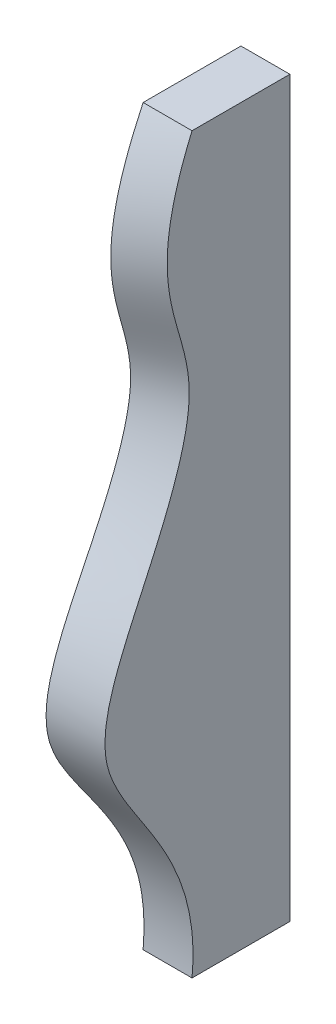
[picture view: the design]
ISO-10303-21;
HEADER;
FILE_DESCRIPTION(('STEP AP214'),'2;1');
FILE_NAME('part.step','',(''),(''),'','','');
FILE_SCHEMA(('AUTOMOTIVE_DESIGN { 1 0 10303 214 1 1 1 1 }'));
ENDSEC;
DATA;
#1=APPLICATION_CONTEXT('core data for automotive mechanical design processes');
#2=APPLICATION_PROTOCOL_DEFINITION('international standard','automotive_design',2000,#1);
#3=PRODUCT_CONTEXT('',#1,'mechanical');
#4=PRODUCT('Part','Part','',(#3));
#5=PRODUCT_RELATED_PRODUCT_CATEGORY('part','',(#4));
#6=PRODUCT_DEFINITION_FORMATION('','',#4);
#7=PRODUCT_DEFINITION_CONTEXT('part definition',#1,'design');
#8=PRODUCT_DEFINITION('design','',#6,#7);
#9=PRODUCT_DEFINITION_SHAPE('','',#8);
#10=(LENGTH_UNIT() NAMED_UNIT(*) SI_UNIT(.MILLI.,.METRE.));
#11=(NAMED_UNIT(*) PLANE_ANGLE_UNIT() SI_UNIT($,.RADIAN.));
#12=(NAMED_UNIT(*) SI_UNIT($,.STERADIAN.) SOLID_ANGLE_UNIT());
#13=UNCERTAINTY_MEASURE_WITH_UNIT(LENGTH_MEASURE(1.E-05),#10,'distance_accuracy_value','');
#14=(GEOMETRIC_REPRESENTATION_CONTEXT(3) GLOBAL_UNCERTAINTY_ASSIGNED_CONTEXT((#13)) GLOBAL_UNIT_ASSIGNED_CONTEXT((#10,
#11,#12)) REPRESENTATION_CONTEXT('',''));
#15=CARTESIAN_POINT('',(0.,0.,0.));
#16=DIRECTION('',(0.,0.,1.));
#17=DIRECTION('',(1.,0.,0.));
#18=AXIS2_PLACEMENT_3D('',#15,#16,#17);
#19=CARTESIAN_POINT('',(350.,375.,253.120113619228));
#20=DIRECTION('',(1.,0.,0.));
#21=DIRECTION('',(0.,0.,-1.));
#22=AXIS2_PLACEMENT_3D('',#19,#20,#21);
#23=PLANE('',#22);
#24=CARTESIAN_POINT('',(350.,375.,100.));
#25=CARTESIAN_POINT('',(350.,373.120513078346,100.80507653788));
#26=CARTESIAN_POINT('',(350.,371.235951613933,101.598369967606));
#27=CARTESIAN_POINT('',(350.,367.454003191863,103.160628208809));
#28=CARTESIAN_POINT('',(350.,365.556603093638,103.929561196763));
#29=CARTESIAN_POINT('',(350.,361.749341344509,105.4409716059));
#30=CARTESIAN_POINT('',(350.,359.839470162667,106.183425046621));
#31=CARTESIAN_POINT('',(350.,356.007596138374,107.639611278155));
#32=CARTESIAN_POINT('',(350.,354.085587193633,108.353328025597));
#33=CARTESIAN_POINT('',(350.,350.229725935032,109.749678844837));
#34=CARTESIAN_POINT('',(350.,348.29587063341,110.432304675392));
#35=CARTESIAN_POINT('',(350.,344.416561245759,111.763993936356));
#36=CARTESIAN_POINT('',(350.,342.471106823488,112.413056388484));
#37=CARTESIAN_POINT('',(350.,338.582432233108,113.670607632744));
#38=CARTESIAN_POINT('',(350.,336.639295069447,114.279352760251));
#39=CARTESIAN_POINT('',(350.,332.741854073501,115.458529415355));
#40=CARTESIAN_POINT('',(350.,330.787552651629,116.02896889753));
#41=CARTESIAN_POINT('',(350.,326.867865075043,117.128727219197));
#42=CARTESIAN_POINT('',(350.,324.902481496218,117.658055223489));
#43=CARTESIAN_POINT('',(350.,320.960675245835,118.672642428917));
#44=CARTESIAN_POINT('',(350.,318.984254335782,119.157908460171));
#45=CARTESIAN_POINT('',(350.,315.020382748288,120.081283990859));
#46=CARTESIAN_POINT('',(350.,313.03293196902,120.519393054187));
#47=CARTESIAN_POINT('',(350.,309.046977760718,121.345234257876));
#48=CARTESIAN_POINT('',(350.,307.048471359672,121.732952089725));
#49=CARTESIAN_POINT('',(350.,303.003435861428,122.461320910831));
#50=CARTESIAN_POINT('',(350.,300.95671871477,122.800931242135));
#51=CARTESIAN_POINT('',(350.,296.853711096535,123.420517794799));
#52=CARTESIAN_POINT('',(350.,294.797418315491,123.700478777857));
#53=CARTESIAN_POINT('',(350.,290.677198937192,124.197048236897));
#54=CARTESIAN_POINT('',(350.,288.613272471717,124.413657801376));
#55=CARTESIAN_POINT('',(350.,284.479758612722,124.780113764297));
#56=CARTESIAN_POINT('',(350.,282.410172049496,124.929969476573));
#57=CARTESIAN_POINT('',(350.,278.267354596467,125.159951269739));
#58=CARTESIAN_POINT('',(350.,276.194124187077,125.240085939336));
#59=CARTESIAN_POINT('',(350.,272.046096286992,125.328271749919));
#60=CARTESIAN_POINT('',(350.,269.971298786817,125.336322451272));
#61=CARTESIAN_POINT('',(350.,265.809538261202,125.278622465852));
#62=CARTESIAN_POINT('',(350.,263.722581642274,125.212402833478));
#63=CARTESIAN_POINT('',(350.,259.551809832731,125.004945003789));
#64=CARTESIAN_POINT('',(350.,257.467995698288,124.863685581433));
#65=CARTESIAN_POINT('',(350.,253.306517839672,124.507067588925));
#66=CARTESIAN_POINT('',(350.,251.228854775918,124.291701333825));
#67=CARTESIAN_POINT('',(350.,247.082496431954,123.789442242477));
#68=CARTESIAN_POINT('',(350.,245.01380004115,123.502558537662));
#69=CARTESIAN_POINT('',(350.,240.887980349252,122.861678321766));
#70=CARTESIAN_POINT('',(350.,238.830851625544,122.507716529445));
#71=CARTESIAN_POINT('',(350.,234.730516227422,121.739032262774));
#72=CARTESIAN_POINT('',(350.,232.687296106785,121.324381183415));
#73=CARTESIAN_POINT('',(350.,229.324667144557,120.596020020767));
#74=CARTESIAN_POINT('',(350.,228.001889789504,120.297687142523));
#75=CARTESIAN_POINT('',(350.,225.361008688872,119.680960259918));
#76=CARTESIAN_POINT('',(350.,224.042904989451,119.362566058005));
#77=CARTESIAN_POINT('',(350.,221.411649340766,118.708615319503));
#78=CARTESIAN_POINT('',(350.,220.098495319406,118.373067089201));
#79=CARTESIAN_POINT('',(350.,217.475944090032,117.687649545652));
#80=CARTESIAN_POINT('',(350.,216.166546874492,117.337780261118));
#81=CARTESIAN_POINT('',(350.,213.550150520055,116.626740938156));
#82=CARTESIAN_POINT('',(350.,212.243152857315,116.265565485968));
#83=CARTESIAN_POINT('',(350.,209.631330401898,115.535463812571));
#84=CARTESIAN_POINT('',(350.,208.326505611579,115.166537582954));
#85=CARTESIAN_POINT('',(350.,205.716806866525,114.424129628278));
#86=CARTESIAN_POINT('',(350.,204.411934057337,114.050643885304));
#87=CARTESIAN_POINT('',(350.,201.802338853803,113.303162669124));
#88=CARTESIAN_POINT('',(350.,200.497616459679,112.929167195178));
#89=CARTESIAN_POINT('',(350.,196.578841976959,111.811199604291));
#90=CARTESIAN_POINT('',(350.,193.963342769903,111.072165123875));
#91=CARTESIAN_POINT('',(350.,190.028741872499,109.996369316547));
#92=CARTESIAN_POINT('',(350.,188.714219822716,109.642950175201));
#93=CARTESIAN_POINT('',(350.,186.08121307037,108.951229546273));
#94=CARTESIAN_POINT('',(350.,184.762728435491,108.612927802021));
#95=CARTESIAN_POINT('',(350.,182.149843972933,107.962512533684));
#96=CARTESIAN_POINT('',(350.,180.855546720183,107.649988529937));
#97=CARTESIAN_POINT('',(350.,178.261875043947,107.046685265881));
#98=CARTESIAN_POINT('',(350.,176.962500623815,106.755905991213));
#99=CARTESIAN_POINT('',(350.,174.35803960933,106.199429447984));
#100=CARTESIAN_POINT('',(350.,173.052951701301,105.933738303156));
#101=CARTESIAN_POINT('',(350.,170.437300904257,105.430717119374));
#102=CARTESIAN_POINT('',(350.,169.126738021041,105.193387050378));
#103=CARTESIAN_POINT('',(350.,166.502305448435,104.750354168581));
#104=CARTESIAN_POINT('',(350.,165.188443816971,104.544603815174));
#105=CARTESIAN_POINT('',(350.,162.555853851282,104.166888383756));
#106=CARTESIAN_POINT('',(350.,161.237125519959,103.9949232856));
#107=CARTESIAN_POINT('',(350.,158.598179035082,103.687308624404));
#108=CARTESIAN_POINT('',(350.,157.277969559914,103.551584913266));
#109=CARTESIAN_POINT('',(350.,154.634210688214,103.317771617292));
#110=CARTESIAN_POINT('',(350.,153.310661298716,103.219681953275));
#111=CARTESIAN_POINT('',(350.,150.663516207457,103.062615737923));
#112=CARTESIAN_POINT('',(350.,149.33992449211,103.003572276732));
#113=CARTESIAN_POINT('',(350.,146.691551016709,102.92521689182));
#114=CARTESIAN_POINT('',(350.,145.366769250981,102.905905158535));
#115=CARTESIAN_POINT('',(350.,142.718527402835,102.907471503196));
#116=CARTESIAN_POINT('',(350.,141.395067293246,102.928310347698));
#117=CARTESIAN_POINT('',(350.,138.749368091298,103.010106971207));
#118=CARTESIAN_POINT('',(350.,137.427128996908,103.071064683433));
#119=CARTESIAN_POINT('',(350.,135.435972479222,103.193010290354));
#120=CARTESIAN_POINT('',(350.,134.766115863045,103.239187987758));
#121=CARTESIAN_POINT('',(350.,133.427178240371,103.341422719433));
#122=CARTESIAN_POINT('',(350.,132.758097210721,103.397479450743));
#123=CARTESIAN_POINT('',(350.,130.752093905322,103.57967287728));
#124=CARTESIAN_POINT('',(350.,129.416427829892,103.719831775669));
#125=CARTESIAN_POINT('',(350.,126.746077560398,104.034330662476));
#126=CARTESIAN_POINT('',(350.,125.411402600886,104.208748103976));
#127=CARTESIAN_POINT('',(350.,122.746472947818,104.588426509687));
#128=CARTESIAN_POINT('',(350.,121.416218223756,104.79368726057));
#129=CARTESIAN_POINT('',(350.,118.756687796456,105.232928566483));
#130=CARTESIAN_POINT('',(350.,117.427425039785,105.466987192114));
#131=CARTESIAN_POINT('',(350.,114.773725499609,105.960958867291));
#132=CARTESIAN_POINT('',(350.,113.449288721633,106.220871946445));
#133=CARTESIAN_POINT('',(350.,110.802364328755,106.765040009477));
#134=CARTESIAN_POINT('',(350.,109.479887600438,107.049347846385));
#135=CARTESIAN_POINT('',(350.,106.839864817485,107.63991702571));
#136=CARTESIAN_POINT('',(350.,105.522318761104,107.946178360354));
#137=CARTESIAN_POINT('',(350.,101.574233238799,108.896112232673));
#138=CARTESIAN_POINT('',(350.,98.9510090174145,109.570359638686));
#139=CARTESIAN_POINT('',(350.,93.7251831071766,110.989597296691));
#140=CARTESIAN_POINT('',(350.,91.1225726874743,111.734555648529));
#141=CARTESIAN_POINT('',(350.,85.8499915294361,113.312392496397));
#142=CARTESIAN_POINT('',(350.,83.1806497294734,114.147367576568));
#143=CARTESIAN_POINT('',(350.,77.866351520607,115.873525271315));
#144=CARTESIAN_POINT('',(350.,75.2213561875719,116.764588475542));
#145=CARTESIAN_POINT('',(350.,69.952539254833,118.59600626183));
#146=CARTESIAN_POINT('',(350.,67.3286938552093,119.536292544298));
#147=CARTESIAN_POINT('',(350.,62.0993206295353,121.460166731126));
#148=CARTESIAN_POINT('',(350.,59.493779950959,122.443719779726));
#149=CARTESIAN_POINT('',(350.,54.2984144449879,124.448835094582));
#150=CARTESIAN_POINT('',(350.,51.7085845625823,125.470384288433));
#151=CARTESIAN_POINT('',(350.,46.5422302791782,127.546711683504));
#152=CARTESIAN_POINT('',(350.,43.9657062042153,128.601490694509));
#153=CARTESIAN_POINT('',(350.,38.6826536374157,130.798510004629));
#154=CARTESIAN_POINT('',(350.,35.976797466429,131.942364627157));
#155=CARTESIAN_POINT('',(350.,30.575370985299,134.256979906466));
#156=CARTESIAN_POINT('',(350.,27.8798051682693,135.427751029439));
#157=CARTESIAN_POINT('',(350.,22.4971061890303,137.791144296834));
#158=CARTESIAN_POINT('',(350.,19.8099764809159,138.983774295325));
#159=CARTESIAN_POINT('',(350.,14.4423010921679,141.385833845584));
#160=CARTESIAN_POINT('',(350.,11.7617575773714,142.595268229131));
#161=CARTESIAN_POINT('',(350.,6.40535766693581,145.025776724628));
#162=CARTESIAN_POINT('',(350.,3.72950224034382,146.246852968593));
#163=CARTESIAN_POINT('',(350.,-1.61951759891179,148.695262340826));
#164=CARTESIAN_POINT('',(350.,-4.2926818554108,149.922595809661));
#165=CARTESIAN_POINT('',(350.,-9.60700695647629,152.363341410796));
#166=CARTESIAN_POINT('',(350.,-12.2481712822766,153.576745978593));
#167=CARTESIAN_POINT('',(350.,-17.5324930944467,155.998195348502));
#168=CARTESIAN_POINT('',(350.,-20.1756502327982,157.206240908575));
#169=CARTESIAN_POINT('',(350.,-25.4667510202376,159.61049346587));
#170=CARTESIAN_POINT('',(350.,-28.1146936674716,160.806702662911));
#171=CARTESIAN_POINT('',(350.,-33.4185081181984,163.180023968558));
#172=CARTESIAN_POINT('',(350.,-36.0743782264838,164.357139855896));
#173=CARTESIAN_POINT('',(350.,-41.3976371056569,166.684025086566));
#174=CARTESIAN_POINT('',(350.,-44.0650241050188,167.833798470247));
#175=CARTESIAN_POINT('',(350.,-49.4154660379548,170.096498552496));
#176=CARTESIAN_POINT('',(350.,-52.09852113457,171.20942486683));
#177=CARTESIAN_POINT('',(350.,-57.224772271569,173.282062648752));
#178=CARTESIAN_POINT('',(350.,-59.666168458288,174.246204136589));
#179=CARTESIAN_POINT('',(350.,-63.3426312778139,175.655331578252));
#180=CARTESIAN_POINT('',(350.,-64.5705891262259,176.11888712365));
#181=CARTESIAN_POINT('',(350.,-67.0316262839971,177.032183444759));
#182=CARTESIAN_POINT('',(350.,-68.2647055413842,177.481924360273));
#183=CARTESIAN_POINT('',(350.,-70.7366637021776,178.366173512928));
#184=CARTESIAN_POINT('',(350.,-71.9755439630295,178.800677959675));
#185=CARTESIAN_POINT('',(350.,-74.4591336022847,179.652659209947));
#186=CARTESIAN_POINT('',(350.,-75.7038428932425,180.070136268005));
#187=CARTESIAN_POINT('',(350.,-78.2042178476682,180.887818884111));
#188=CARTESIAN_POINT('',(350.,-79.4599072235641,181.287952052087));
#189=CARTESIAN_POINT('',(350.,-81.9777631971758,182.067232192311));
#190=CARTESIAN_POINT('',(350.,-83.2399296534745,182.446379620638));
#191=CARTESIAN_POINT('',(350.,-85.7708333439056,183.18148401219));
#192=CARTESIAN_POINT('',(350.,-87.0395696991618,183.53744399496));
#193=CARTESIAN_POINT('',(350.,-89.5839467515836,184.223888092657));
#194=CARTESIAN_POINT('',(350.,-90.8595875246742,184.554371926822));
#195=CARTESIAN_POINT('',(350.,-93.4175328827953,185.187261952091));
#196=CARTESIAN_POINT('',(350.,-94.6998359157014,185.489674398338));
#197=CARTESIAN_POINT('',(350.,-97.2712641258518,186.063782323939));
#198=CARTESIAN_POINT('',(350.,-98.5603890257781,186.335479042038));
#199=CARTESIAN_POINT('',(350.,-101.248551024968,186.865648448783));
#200=CARTESIAN_POINT('',(350.,-102.648141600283,187.121330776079));
#201=CARTESIAN_POINT('',(350.,-105.454585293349,187.58968211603));
#202=CARTESIAN_POINT('',(350.,-106.861438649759,187.802349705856));
#203=CARTESIAN_POINT('',(350.,-109.681510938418,188.180627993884));
#204=CARTESIAN_POINT('',(350.,-111.094729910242,188.34623839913));
#205=CARTESIAN_POINT('',(350.,-113.92664311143,188.626283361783));
#206=CARTESIAN_POINT('',(350.,-115.345338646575,188.74070484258));
#207=CARTESIAN_POINT('',(350.,-118.174518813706,188.913417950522));
#208=CARTESIAN_POINT('',(350.,-119.584975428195,188.972161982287));
#209=CARTESIAN_POINT('',(350.,-122.407267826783,189.031152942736));
#210=CARTESIAN_POINT('',(350.,-123.81910370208,189.031395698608));
#211=CARTESIAN_POINT('',(350.,-126.641075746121,188.969641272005));
#212=CARTESIAN_POINT('',(350.,-128.051212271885,188.90766096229));
#213=CARTESIAN_POINT('',(350.,-130.866759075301,188.718172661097));
#214=CARTESIAN_POINT('',(350.,-132.272170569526,188.590683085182));
#215=CARTESIAN_POINT('',(350.,-134.804115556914,188.298728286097));
#216=CARTESIAN_POINT('',(350.,-135.932034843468,188.146176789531));
#217=CARTESIAN_POINT('',(350.,-138.181044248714,187.795556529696));
#218=CARTESIAN_POINT('',(350.,-139.302133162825,187.597479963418));
#219=CARTESIAN_POINT('',(350.,-140.976902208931,187.26574452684));
#220=CARTESIAN_POINT('',(350.,-141.534060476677,187.149384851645));
#221=CARTESIAN_POINT('',(350.,-142.645828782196,186.905037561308));
#222=CARTESIAN_POINT('',(350.,-143.200438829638,186.777049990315));
#223=CARTESIAN_POINT('',(350.,-144.306943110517,186.509594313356));
#224=CARTESIAN_POINT('',(350.,-144.858837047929,186.370124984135));
#225=CARTESIAN_POINT('',(350.,-145.95973729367,186.080243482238));
#226=CARTESIAN_POINT('',(350.,-146.508743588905,185.929831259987));
#227=CARTESIAN_POINT('',(350.,-148.15112948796,185.462949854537));
#228=CARTESIAN_POINT('',(350.,-149.24007781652,185.130786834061));
#229=CARTESIAN_POINT('',(350.,-151.415739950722,184.42557964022));
#230=CARTESIAN_POINT('',(350.,-152.502339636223,184.052185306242));
#231=CARTESIAN_POINT('',(350.,-154.123000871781,183.466726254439));
#232=CARTESIAN_POINT('',(350.,-154.661684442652,183.267344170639));
#233=CARTESIAN_POINT('',(350.,-155.736029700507,182.860598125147));
#234=CARTESIAN_POINT('',(350.,-156.271691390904,182.653234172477));
#235=CARTESIAN_POINT('',(350.,-157.874220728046,182.019720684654));
#236=CARTESIAN_POINT('',(350.,-158.936595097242,181.582163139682));
#237=CARTESIAN_POINT('',(350.,-161.049519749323,180.679762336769));
#238=CARTESIAN_POINT('',(350.,-162.10007120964,180.214921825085));
#239=CARTESIAN_POINT('',(350.,-164.189494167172,179.260981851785));
#240=CARTESIAN_POINT('',(350.,-165.228370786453,178.771893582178));
#241=CARTESIAN_POINT('',(350.,-167.956961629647,177.451999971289));
#242=CARTESIAN_POINT('',(350.,-169.637781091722,176.602787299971));
#243=CARTESIAN_POINT('',(350.,-172.974365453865,174.856338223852));
#244=CARTESIAN_POINT('',(350.,-174.630127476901,173.95909635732));
#245=CARTESIAN_POINT('',(350.,-177.919555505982,172.126130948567));
#246=CARTESIAN_POINT('',(350.,-179.553227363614,171.190417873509));
#247=CARTESIAN_POINT('',(350.,-182.802500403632,169.288357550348));
#248=CARTESIAN_POINT('',(350.,-184.418102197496,168.322011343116));
#249=CARTESIAN_POINT('',(350.,-187.637374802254,166.364149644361));
#250=CARTESIAN_POINT('',(350.,-189.241023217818,165.372597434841));
#251=CARTESIAN_POINT('',(350.,-192.437327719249,163.371952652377));
#252=CARTESIAN_POINT('',(350.,-194.029983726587,162.362859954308));
#253=CARTESIAN_POINT('',(350.,-197.210413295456,160.330819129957));
#254=CARTESIAN_POINT('',(350.,-198.798173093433,159.307849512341));
#255=CARTESIAN_POINT('',(350.,-201.969050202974,157.254766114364));
#256=CARTESIAN_POINT('',(350.,-203.552167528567,156.224652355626));
#257=CARTESIAN_POINT('',(350.,-206.718919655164,154.16028105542));
#258=CARTESIAN_POINT('',(350.,-208.302551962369,153.126019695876));
#259=CARTESIAN_POINT('',(350.,-211.470762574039,151.058943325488));
#260=CARTESIAN_POINT('',(350.,-213.05534087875,150.02612831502));
#261=CARTESIAN_POINT('',(350.,-216.229482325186,147.964763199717));
#262=CARTESIAN_POINT('',(350.,-217.819048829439,146.936218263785));
#263=CARTESIAN_POINT('',(350.,-221.003906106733,144.888016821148));
#264=CARTESIAN_POINT('',(350.,-222.59919687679,143.868360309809));
#265=CARTESIAN_POINT('',(350.,-225.78214597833,141.851140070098));
#266=CARTESIAN_POINT('',(350.,-227.369729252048,140.853458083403));
#267=CARTESIAN_POINT('',(350.,-230.55438930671,138.873341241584));
#268=CARTESIAN_POINT('',(350.,-232.151466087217,137.890906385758));
#269=CARTESIAN_POINT('',(350.,-235.35619372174,135.944690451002));
#270=CARTESIAN_POINT('',(350.,-236.963840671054,134.980902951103));
#271=CARTESIAN_POINT('',(350.,-240.191711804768,133.074597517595));
#272=CARTESIAN_POINT('',(350.,-241.811935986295,132.132079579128));
#273=CARTESIAN_POINT('',(350.,-245.064242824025,130.272332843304));
#274=CARTESIAN_POINT('',(350.,-246.696308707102,129.355074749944));
#275=CARTESIAN_POINT('',(350.,-249.975275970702,127.547478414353));
#276=CARTESIAN_POINT('',(350.,-251.622177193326,126.65713988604));
#277=CARTESIAN_POINT('',(350.,-254.929230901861,124.907408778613));
#278=CARTESIAN_POINT('',(350.,-256.589360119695,124.047972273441));
#279=CARTESIAN_POINT('',(350.,-259.925917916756,122.361311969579));
#280=CARTESIAN_POINT('',(350.,-261.602346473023,121.534088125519));
#281=CARTESIAN_POINT('',(350.,-264.970012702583,119.915346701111));
#282=CARTESIAN_POINT('',(350.,-266.661231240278,119.123789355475));
#283=CARTESIAN_POINT('',(350.,-270.060592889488,117.577835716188));
#284=CARTESIAN_POINT('',(350.,-271.76873607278,116.823439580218));
#285=CARTESIAN_POINT('',(350.,-275.201636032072,115.3542994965));
#286=CARTESIAN_POINT('',(350.,-276.926389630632,114.639548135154));
#287=CARTESIAN_POINT('',(350.,-280.392559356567,113.251781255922));
#288=CARTESIAN_POINT('',(350.,-282.1339752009,112.57876503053));
#289=CARTESIAN_POINT('',(350.,-286.584350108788,110.922528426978));
#290=CARTESIAN_POINT('',(350.,-289.304656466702,109.969566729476));
#291=CARTESIAN_POINT('',(350.,-294.783311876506,108.17429983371));
#292=CARTESIAN_POINT('',(350.,-297.541682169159,107.332059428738));
#293=CARTESIAN_POINT('',(350.,-303.092196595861,105.764275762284));
#294=CARTESIAN_POINT('',(350.,-305.884348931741,105.03876147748));
#295=CARTESIAN_POINT('',(350.,-311.497628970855,103.708929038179));
#296=CARTESIAN_POINT('',(350.,-314.318758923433,103.104620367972));
#297=CARTESIAN_POINT('',(350.,-320.000314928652,102.017157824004));
#298=CARTESIAN_POINT('',(350.,-322.860871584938,101.534685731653));
#299=CARTESIAN_POINT('',(350.,-328.60035899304,100.69666971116));
#300=CARTESIAN_POINT('',(350.,-331.479288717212,100.341118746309));
#301=CARTESIAN_POINT('',(350.,-337.249290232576,99.7569235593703));
#302=CARTESIAN_POINT('',(350.,-340.140359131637,99.5282506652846));
#303=CARTESIAN_POINT('',(350.,-345.928436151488,99.1963682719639));
#304=CARTESIAN_POINT('',(350.,-348.825440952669,99.0931014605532));
#305=CARTESIAN_POINT('',(350.,-353.021657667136,99.0323729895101));
#306=CARTESIAN_POINT('',(350.,-354.320338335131,99.0258969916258));
#307=CARTESIAN_POINT('',(350.,-356.917343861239,99.03726220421));
#308=CARTESIAN_POINT('',(350.,-358.215668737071,99.0550983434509));
#309=CARTESIAN_POINT('',(350.,-360.811638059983,99.1147457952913));
#310=CARTESIAN_POINT('',(350.,-362.109282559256,99.1565548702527));
#311=CARTESIAN_POINT('',(350.,-364.696506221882,99.2634850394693));
#312=CARTESIAN_POINT('',(350.,-365.986090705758,99.3284774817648));
#313=CARTESIAN_POINT('',(350.,-368.564007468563,99.4814294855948));
#314=CARTESIAN_POINT('',(350.,-369.852339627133,99.5693910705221));
#315=CARTESIAN_POINT('',(350.,-372.427466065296,99.7678766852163));
#316=CARTESIAN_POINT('',(350.,-373.714260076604,99.8784041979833));
#317=CARTESIAN_POINT('',(350.,-375.,100.));
#318=B_SPLINE_CURVE_WITH_KNOTS('',3,(#24,#25,#26,#27,#28,#29,#30,#31,#32,#33,#34,#35,#36,#37,
#38,#39,#40,#41,#42,#43,#44,#45,#46,#47,#48,#49,#50,#51,#52,#53,#54,#55,#56,#57,#58,#59,#60,#61,
#62,#63,#64,#65,#66,#67,#68,#69,#70,#71,#72,#73,#74,#75,#76,#77,#78,#79,#80,#81,#82,#83,#84,#85,
#86,#87,#88,#89,#90,#91,#92,#93,#94,#95,#96,#97,#98,#99,#100,#101,#102,#103,#104,#105,#106,#107,
#108,#109,#110,#111,#112,#113,#114,#115,#116,#117,#118,#119,#120,#121,#122,#123,#124,#125,#126,
#127,#128,#129,#130,#131,#132,#133,#134,#135,#136,#137,#138,#139,#140,#141,#142,#143,#144,#145,
#146,#147,#148,#149,#150,#151,#152,#153,#154,#155,#156,#157,#158,#159,#160,#161,#162,#163,#164,
#165,#166,#167,#168,#169,#170,#171,#172,#173,#174,#175,#176,#177,#178,#179,#180,#181,#182,#183,
#184,#185,#186,#187,#188,#189,#190,#191,#192,#193,#194,#195,#196,#197,#198,#199,#200,#201,#202,
#203,#204,#205,#206,#207,#208,#209,#210,#211,#212,#213,#214,#215,#216,#217,#218,#219,#220,#221,
#222,#223,#224,#225,#226,#227,#228,#229,#230,#231,#232,#233,#234,#235,#236,#237,#238,#239,#240,
#241,#242,#243,#244,#245,#246,#247,#248,#249,#250,#251,#252,#253,#254,#255,#256,#257,#258,#259,
#260,#261,#262,#263,#264,#265,#266,#267,#268,#269,#270,#271,#272,#273,#274,#275,#276,#277,#278,
#279,#280,#281,#282,#283,#284,#285,#286,#287,#288,#289,#290,#291,#292,#293,#294,#295,#296,#297,
#298,#299,#300,#301,#302,#303,#304,#305,#306,#307,#308,#309,#310,#311,#312,#313,#314,#315,#316,
#317),.UNSPECIFIED.,.F.,.F.,(4,2,2,2,2,2,2,2,2,2,2,2,2,2,2,2,2,2,2,2,2,2,2,2,2,2,2,2,2,2,2,2,2,
2,2,2,2,2,2,2,2,2,2,2,2,2,2,2,2,2,2,2,2,2,2,2,2,2,2,2,2,2,2,2,2,2,2,2,2,2,2,2,2,2,2,2,2,2,2,2,2,
2,2,2,2,2,2,2,2,2,2,2,2,2,2,2,2,2,2,2,2,2,2,2,2,2,2,2,2,2,2,2,2,2,2,2,2,2,2,2,2,2,2,2,2,2,2,2,2,
2,2,2,2,2,2,2,2,2,2,2,2,2,2,2,2,2,4),(0.,6.13396569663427,12.2756392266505,18.4227404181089,
24.573227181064,30.7253348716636,36.8776217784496,42.9860347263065,49.0931752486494,
55.1989504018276,61.3037774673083,67.4086609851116,73.5152742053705,79.7385472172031,
85.9634081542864,92.1881621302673,98.4120473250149,104.635165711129,110.858322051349,
117.120993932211,123.385438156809,129.650532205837,135.91482672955,142.175887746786,
148.429641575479,152.497498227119,156.56539494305,160.631340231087,164.697277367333,
168.765192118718,172.833111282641,176.904919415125,180.976733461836,189.130234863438,
193.213773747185,197.297243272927,201.291567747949,205.285889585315,209.281183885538,
213.276473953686,217.265689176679,221.254902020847,225.235889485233,229.216868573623,
233.191008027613,237.16516652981,241.13544362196,245.105714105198,247.119988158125,
249.134200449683,253.162674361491,257.200363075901,261.238023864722,265.286882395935,
269.335745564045,273.393613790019,277.451480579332,285.575675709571,293.69622299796,
302.086110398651,310.458703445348,318.819972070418,327.174623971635,335.526427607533,
343.878434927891,352.691353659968,361.507759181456,370.327397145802,379.149625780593,
387.973502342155,396.797864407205,405.517549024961,414.235958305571,422.952715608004,
431.667726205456,440.381440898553,449.095246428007,456.969394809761,460.906950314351,
464.844465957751,468.782954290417,472.72138372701,476.674919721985,480.628369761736,
484.581303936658,488.534281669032,492.486376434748,496.438311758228,500.705954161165,
504.973737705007,509.241547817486,513.510447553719,517.74435541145,521.978565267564,
526.211627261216,530.443499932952,533.857219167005,537.271523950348,538.978959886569,
540.68638934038,542.394000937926,544.101620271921,547.516236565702,550.962480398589,
552.685620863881,554.408759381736,557.855156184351,561.301206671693,564.745681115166,
570.394147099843,576.043256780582,581.690839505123,587.338230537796,592.994381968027,
598.650573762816,604.316847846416,609.983104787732,615.657459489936,621.331815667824,
627.011730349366,632.691642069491,638.316705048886,643.941767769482,649.564857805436,
655.18794655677,660.804212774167,666.420419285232,672.028298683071,677.636170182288,
683.237626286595,688.839106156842,694.439534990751,700.039868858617,708.684660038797,
717.334487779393,725.9864594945,734.639107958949,743.339152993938,752.03871560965,
760.736311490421,769.429930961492,773.325846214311,777.220948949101,781.115688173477,
784.989142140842,788.862937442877,792.737331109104),.UNSPECIFIED.);
#319=CARTESIAN_POINT('',(350.,375.,100.));
#320=VERTEX_POINT('',#319);
#321=CARTESIAN_POINT('',(350.,-375.,100.));
#322=VERTEX_POINT('',#321);
#323=EDGE_CURVE('E88',#320,#322,#318,.T.);
#324=ORIENTED_EDGE('',*,*,#323,.T.);
#325=DIRECTION('',(0.,0.,-1.));
#326=VECTOR('',#325,1.);
#327=CARTESIAN_POINT('',(350.,-375.,253.120113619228));
#328=LINE('',#327,#326);
#329=CARTESIAN_POINT('',(350.,-375.,0.));
#330=VERTEX_POINT('',#329);
#331=EDGE_CURVE('E50',#322,#330,#328,.T.);
#332=ORIENTED_EDGE('',*,*,#331,.T.);
#333=DIRECTION('',(0.,-1.,0.));
#334=VECTOR('',#333,1.);
#335=CARTESIAN_POINT('',(350.,375.,0.));
#336=LINE('',#335,#334);
#337=CARTESIAN_POINT('',(350.,375.,0.));
#338=VERTEX_POINT('',#337);
#339=EDGE_CURVE('E87',#338,#330,#336,.T.);
#340=ORIENTED_EDGE('',*,*,#339,.F.);
#341=DIRECTION('',(0.,0.,-1.));
#342=VECTOR('',#341,1.);
#343=CARTESIAN_POINT('',(350.,375.,253.120113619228));
#344=LINE('',#343,#342);
#345=EDGE_CURVE('E65',#320,#338,#344,.T.);
#346=ORIENTED_EDGE('',*,*,#345,.F.);
#347=EDGE_LOOP('',(#324,#332,#340,#346));
#348=FACE_BOUND('',#347,.T.);
#349=ADVANCED_FACE('F35',(#348),#23,.T.);
#350=CARTESIAN_POINT('',(0.,0.,0.));
#351=DIRECTION('',(0.,0.,-1.));
#352=DIRECTION('',(-1.,0.,0.));
#353=AXIS2_PLACEMENT_3D('',#350,#351,#352);
#354=PLANE('',#353);
#355=DIRECTION('',(1.,0.,0.));
#356=VECTOR('',#355,1.);
#357=CARTESIAN_POINT('',(-750.,-375.,0.));
#358=LINE('',#357,#356);
#359=CARTESIAN_POINT('',(300.,-375.,0.));
#360=VERTEX_POINT('',#359);
#361=EDGE_CURVE('E79',#360,#330,#358,.T.);
#362=ORIENTED_EDGE('',*,*,#361,.F.);
#363=DIRECTION('',(0.,1.,0.));
#364=VECTOR('',#363,1.);
#365=CARTESIAN_POINT('',(300.,375.,0.));
#366=LINE('',#365,#364);
#367=CARTESIAN_POINT('',(300.,375.,0.));
#368=VERTEX_POINT('',#367);
#369=EDGE_CURVE('E157',#360,#368,#366,.T.);
#370=ORIENTED_EDGE('',*,*,#369,.T.);
#371=DIRECTION('',(-1.,0.,0.));
#372=VECTOR('',#371,1.);
#373=CARTESIAN_POINT('',(-750.,375.,0.));
#374=LINE('',#373,#372);
#375=EDGE_CURVE('E93',#338,#368,#374,.T.);
#376=ORIENTED_EDGE('',*,*,#375,.F.);
#377=ORIENTED_EDGE('',*,*,#339,.T.);
#378=EDGE_LOOP('',(#362,#370,#376,#377));
#379=FACE_BOUND('',#378,.T.);
#380=ADVANCED_FACE('F91',(#379),#354,.T.);
#381=CARTESIAN_POINT('',(750.,-375.,100.));
#382=CARTESIAN_POINT('',(750.,-302.078506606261,100.));
#383=CARTESIAN_POINT('',(750.,-224.483786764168,100.));
#384=CARTESIAN_POINT('',(750.,-61.5160152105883,100.));
#385=CARTESIAN_POINT('',(750.,39.4445673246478,100.));
#386=CARTESIAN_POINT('',(750.,211.849847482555,100.));
#387=CARTESIAN_POINT('',(750.,298.882075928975,100.));
#388=CARTESIAN_POINT('',(750.,375.,100.));
#389=CARTESIAN_POINT('',(669.085175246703,-375.,100.));
#390=CARTESIAN_POINT('',(669.085175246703,-302.078506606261,100.));
#391=CARTESIAN_POINT('',(669.085175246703,-234.282472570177,121.198481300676));
#392=CARTESIAN_POINT('',(669.085175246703,-62.2283080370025,120.288550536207));
#393=CARTESIAN_POINT('',(669.085175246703,68.0647781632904,82.7868169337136));
#394=CARTESIAN_POINT('',(669.085175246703,240.312514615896,73.0426687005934));
#395=CARTESIAN_POINT('',(669.085175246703,298.882075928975,100.));
#396=CARTESIAN_POINT('',(669.085175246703,375.,100.));
#397=CARTESIAN_POINT('',(500.445116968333,-375.,100.));
#398=CARTESIAN_POINT('',(517.991528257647,-284.627602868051,95.5040591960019));
#399=CARTESIAN_POINT('',(530.038001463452,-221.673003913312,150.719602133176));
#400=CARTESIAN_POINT('',(473.74510655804,-71.7416270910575,167.060530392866));
#401=CARTESIAN_POINT('',(387.213321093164,45.6135081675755,91.591323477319));
#402=CARTESIAN_POINT('',(378.694107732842,207.638743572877,66.6461848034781));
#403=CARTESIAN_POINT('',(433.17831170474,253.396603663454,122.492891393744));
#404=CARTESIAN_POINT('',(500.445116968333,375.,100.));
#405=CARTESIAN_POINT('',(285.091607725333,-375.,100.));
#406=CARTESIAN_POINT('',(309.270321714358,-264.297524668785,86.4064578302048));
#407=CARTESIAN_POINT('',(325.856840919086,-200.08226970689,164.07204721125));
#408=CARTESIAN_POINT('',(247.47112957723,-80.9425320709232,234.992870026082));
#409=CARTESIAN_POINT('',(127.240382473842,2.40271344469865,186.756001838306));
#410=CARTESIAN_POINT('',(115.567806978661,152.518027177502,151.057444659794));
#411=CARTESIAN_POINT('',(191.428893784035,202.025100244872,189.039851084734));
#412=CARTESIAN_POINT('',(285.091607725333,375.,100.));
#413=CARTESIAN_POINT('',(47.4554331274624,-375.,100.));
#414=CARTESIAN_POINT('',(51.0669239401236,-278.639867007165,99.5141662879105));
#415=CARTESIAN_POINT('',(52.9210710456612,-231.452124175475,201.325948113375));
#416=CARTESIAN_POINT('',(3.18149891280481,-90.8615864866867,272.445475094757));
#417=CARTESIAN_POINT('',(-61.0346058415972,45.7948958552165,186.157760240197));
#418=CARTESIAN_POINT('',(-59.6612105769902,205.286893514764,133.941969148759));
#419=CARTESIAN_POINT('',(-11.8049718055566,220.40073671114,189.8209162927));
#420=CARTESIAN_POINT('',(47.4554331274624,375.,100.));
#421=CARTESIAN_POINT('',(-175.903454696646,-375.,100.));
#422=CARTESIAN_POINT('',(-199.823715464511,-320.588060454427,126.731848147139));
#423=CARTESIAN_POINT('',(-216.967937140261,-300.821135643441,242.921959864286));
#424=CARTESIAN_POINT('',(-184.265304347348,-55.1410097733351,206.147478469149));
#425=CARTESIAN_POINT('',(-119.865061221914,249.096629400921,-32.5779079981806));
#426=CARTESIAN_POINT('',(-104.641938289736,431.262460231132,-94.4845569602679));
#427=CARTESIAN_POINT('',(-136.623034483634,348.137040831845,60.785640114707));
#428=CARTESIAN_POINT('',(-175.903454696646,375.,100.));
#429=CARTESIAN_POINT('',(-355.235514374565,-375.,100.));
#430=CARTESIAN_POINT('',(-319.200833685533,-282.590755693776,58.2859511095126));
#431=CARTESIAN_POINT('',(-293.075279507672,-226.888141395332,104.97090627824));
#432=CARTESIAN_POINT('',(-324.119079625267,-68.6572837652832,122.102733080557));
#433=CARTESIAN_POINT('',(-398.972481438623,73.039345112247,53.3701087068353));
#434=CARTESIAN_POINT('',(-423.398679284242,233.384819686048,47.4380317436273));
#435=CARTESIAN_POINT('',(-392.720188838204,253.575952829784,124.952096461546));
#436=CARTESIAN_POINT('',(-355.235514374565,375.,100.));
#437=CARTESIAN_POINT('',(-536.684515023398,-375.,100.));
#438=CARTESIAN_POINT('',(-494.827225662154,-277.129657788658,52.0422385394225));
#439=CARTESIAN_POINT('',(-464.573647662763,-205.017596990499,67.039018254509));
#440=CARTESIAN_POINT('',(-506.334367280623,-72.2467511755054,96.5036749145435));
#441=CARTESIAN_POINT('',(-600.216684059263,9.35641022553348,95.9941925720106));
#442=CARTESIAN_POINT('',(-628.122542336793,166.946160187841,106.349064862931));
#443=CARTESIAN_POINT('',(-587.011939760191,237.095914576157,138.331902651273));
#444=CARTESIAN_POINT('',(-536.684515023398,375.,100.));
#445=CARTESIAN_POINT('',(-644.685568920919,-375.,100.));
#446=CARTESIAN_POINT('',(-644.685568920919,-302.078506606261,100.));
#447=CARTESIAN_POINT('',(-644.685568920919,-237.237234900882,127.59081546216));
#448=CARTESIAN_POINT('',(-644.685568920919,-62.4430976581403,126.406497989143));
#449=CARTESIAN_POINT('',(-644.685568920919,76.6951111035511,77.5962366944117));
#450=CARTESIAN_POINT('',(-644.685568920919,248.895340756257,64.9137717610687));
#451=CARTESIAN_POINT('',(-644.685568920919,298.882075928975,100.));
#452=CARTESIAN_POINT('',(-644.685568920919,375.,100.));
#453=CARTESIAN_POINT('',(-750.,-375.,100.));
#454=CARTESIAN_POINT('',(-750.,-302.078506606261,100.));
#455=CARTESIAN_POINT('',(-750.,-224.483786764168,100.));
#456=CARTESIAN_POINT('',(-750.,-61.5160152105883,100.));
#457=CARTESIAN_POINT('',(-750.,39.4445673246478,100.));
#458=CARTESIAN_POINT('',(-750.,211.849847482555,100.));
#459=CARTESIAN_POINT('',(-750.,298.882075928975,100.));
#460=CARTESIAN_POINT('',(-750.,375.,100.));
#461=B_SPLINE_SURFACE_WITH_KNOTS('',3,3,((#381,#382,#383,#384,#385,#386,#387,#388),(#389,#390,
#391,#392,#393,#394,#395,#396),(#397,#398,#399,#400,#401,#402,#403,#404),(#405,#406,#407,#408,
#409,#410,#411,#412),(#413,#414,#415,#416,#417,#418,#419,#420),(#421,#422,#423,#424,#425,#426,
#427,#428),(#429,#430,#431,#432,#433,#434,#435,#436),(#437,#438,#439,#440,#441,#442,#443,#444),
(#445,#446,#447,#448,#449,#450,#451,#452),(#453,#454,#455,#456,#457,#458,#459,#460)),
.UNSPECIFIED.,.F.,.F.,.F.,(4,1,1,1,1,1,1,4),(4,1,1,1,1,4),(0.,0.161829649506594,
0.33728011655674,0.430707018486,0.637101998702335,0.783997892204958,0.789371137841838,1.),(0.,
0.291685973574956,0.310378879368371,0.65187108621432,0.695528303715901,1.),.UNSPECIFIED.);
#462=CARTESIAN_POINT('',(300.,-375.,100.));
#463=CARTESIAN_POINT('',(300.,-373.138407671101,99.8182393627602));
#464=CARTESIAN_POINT('',(300.,-371.274425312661,99.6605483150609));
#465=CARTESIAN_POINT('',(300.,-367.541905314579,99.394684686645));
#466=CARTESIAN_POINT('',(300.,-365.673365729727,99.2865394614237));
#467=CARTESIAN_POINT('',(300.,-361.93340394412,99.121323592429));
#468=CARTESIAN_POINT('',(300.,-360.061981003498,99.0642695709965));
#469=CARTESIAN_POINT('',(300.,-356.31796066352,99.0025972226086));
#470=CARTESIAN_POINT('',(300.,-354.445363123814,98.9979873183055));
#471=CARTESIAN_POINT('',(300.,-350.700697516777,99.0423846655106));
#472=CARTESIAN_POINT('',(300.,-348.828629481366,99.0913946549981));
#473=CARTESIAN_POINT('',(300.,-345.086732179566,99.2440069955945));
#474=CARTESIAN_POINT('',(300.,-343.216902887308,99.347608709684));
#475=CARTESIAN_POINT('',(300.,-339.499672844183,99.6088576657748));
#476=CARTESIAN_POINT('',(300.,-337.652233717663,99.7659581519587));
#477=CARTESIAN_POINT('',(300.,-333.963080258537,100.134889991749));
#478=CARTESIAN_POINT('',(300.,-332.121365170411,100.346713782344));
#479=CARTESIAN_POINT('',(300.,-328.445346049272,100.825315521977));
#480=CARTESIAN_POINT('',(300.,-326.611041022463,101.092085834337));
#481=CARTESIAN_POINT('',(300.,-322.951486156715,101.680535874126));
#482=CARTESIAN_POINT('',(300.,-321.126235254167,102.002208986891));
#483=CARTESIAN_POINT('',(300.,-317.486383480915,102.700142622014));
#484=CARTESIAN_POINT('',(300.,-315.671781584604,103.076397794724));
#485=CARTESIAN_POINT('',(300.,-312.054794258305,103.882875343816));
#486=CARTESIAN_POINT('',(300.,-310.252407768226,104.313092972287));
#487=CARTESIAN_POINT('',(300.,-306.297354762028,105.319185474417));
#488=CARTESIAN_POINT('',(300.,-304.147694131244,105.906912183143));
#489=CARTESIAN_POINT('',(300.,-299.870013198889,107.157165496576));
#490=CARTESIAN_POINT('',(300.,-297.74199536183,107.819700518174));
#491=CARTESIAN_POINT('',(300.,-293.509493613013,109.216977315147));
#492=CARTESIAN_POINT('',(300.,-291.405012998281,109.951729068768));
#493=CARTESIAN_POINT('',(300.,-287.221311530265,111.490277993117));
#494=CARTESIAN_POINT('',(300.,-285.142092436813,112.294079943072));
#495=CARTESIAN_POINT('',(300.,-281.010437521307,113.96701391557));
#496=CARTESIAN_POINT('',(300.,-278.957998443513,114.836137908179));
#497=CARTESIAN_POINT('',(300.,-274.879617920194,116.636175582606));
#498=CARTESIAN_POINT('',(300.,-272.853685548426,117.567109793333));
#499=CARTESIAN_POINT('',(300.,-268.829461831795,119.48616142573));
#500=CARTESIAN_POINT('',(300.,-266.831166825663,120.474271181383));
#501=CARTESIAN_POINT('',(300.,-262.86166084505,122.503338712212));
#502=CARTESIAN_POINT('',(300.,-260.890449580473,123.544295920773));
#503=CARTESIAN_POINT('',(300.,-256.97439538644,125.674432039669));
#504=CARTESIAN_POINT('',(300.,-255.02955144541,126.763609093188));
#505=CARTESIAN_POINT('',(300.,-251.165371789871,128.98526131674));
#506=CARTESIAN_POINT('',(300.,-249.24603057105,130.117726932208));
#507=CARTESIAN_POINT('',(300.,-244.834934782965,132.781189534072));
#508=CARTESIAN_POINT('',(300.,-242.351635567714,134.326185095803));
#509=CARTESIAN_POINT('',(300.,-237.420936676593,137.471786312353));
#510=CARTESIAN_POINT('',(300.,-234.973534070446,139.072387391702));
#511=CARTESIAN_POINT('',(300.,-230.107923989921,142.31859584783));
#512=CARTESIAN_POINT('',(300.,-227.689724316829,143.964214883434));
#513=CARTESIAN_POINT('',(300.,-222.875422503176,147.289209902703));
#514=CARTESIAN_POINT('',(300.,-220.4793287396,148.968597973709));
#515=CARTESIAN_POINT('',(300.,-215.701591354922,152.349090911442));
#516=CARTESIAN_POINT('',(300.,-213.319951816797,154.050201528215));
#517=CARTESIAN_POINT('',(300.,-209.746525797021,156.612262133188));
#518=CARTESIAN_POINT('',(300.,-208.552443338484,157.470022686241));
#519=CARTESIAN_POINT('',(300.,-206.164580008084,159.185963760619));
#520=CARTESIAN_POINT('',(300.,-204.9707991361,160.044144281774));
#521=CARTESIAN_POINT('',(300.,-202.582491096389,161.758934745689));
#522=CARTESIAN_POINT('',(300.,-201.387964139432,162.615544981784));
#523=CARTESIAN_POINT('',(300.,-198.99653886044,164.325447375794));
#524=CARTESIAN_POINT('',(300.,-197.799640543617,165.178739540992));
#525=CARTESIAN_POINT('',(300.,-195.402543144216,166.879573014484));
#526=CARTESIAN_POINT('',(300.,-194.202345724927,167.727116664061));
#527=CARTESIAN_POINT('',(300.,-191.796610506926,169.414598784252));
#528=CARTESIAN_POINT('',(300.,-190.59107271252,170.254537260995));
#529=CARTESIAN_POINT('',(300.,-188.173628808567,171.923988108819));
#530=CARTESIAN_POINT('',(300.,-186.961725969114,172.753505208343));
#531=CARTESIAN_POINT('',(300.,-184.529315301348,174.399858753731));
#532=CARTESIAN_POINT('',(300.,-183.308807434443,175.216695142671));
#533=CARTESIAN_POINT('',(300.,-180.857541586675,176.834684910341));
#534=CARTESIAN_POINT('',(300.,-179.626784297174,177.635839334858));
#535=CARTESIAN_POINT('',(300.,-177.153161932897,179.219243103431));
#536=CARTESIAN_POINT('',(300.,-175.910297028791,180.00149271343));
#537=CARTESIAN_POINT('',(300.,-173.733045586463,181.344539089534));
#538=CARTESIAN_POINT('',(300.,-172.801788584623,181.910408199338));
#539=CARTESIAN_POINT('',(300.,-170.930861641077,183.028054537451));
#540=CARTESIAN_POINT('',(300.,-169.991191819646,183.579831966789));
#541=CARTESIAN_POINT('',(300.,-168.102469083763,184.667628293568));
#542=CARTESIAN_POINT('',(300.,-167.153414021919,185.203643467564));
#543=CARTESIAN_POINT('',(300.,-165.245420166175,186.257813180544));
#544=CARTESIAN_POINT('',(300.,-164.286481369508,186.775967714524));
#545=CARTESIAN_POINT('',(300.,-162.357465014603,187.792578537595));
#546=CARTESIAN_POINT('',(300.,-161.387381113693,188.291022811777));
#547=CARTESIAN_POINT('',(300.,-159.436023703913,189.265549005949));
#548=CARTESIAN_POINT('',(300.,-158.454750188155,189.741630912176));
#549=CARTESIAN_POINT('',(300.,-156.489864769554,190.664511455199));
#550=CARTESIAN_POINT('',(300.,-155.506363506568,191.111545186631));
#551=CARTESIAN_POINT('',(300.,-153.527465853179,191.978537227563));
#552=CARTESIAN_POINT('',(300.,-152.532069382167,192.398495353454));
#553=CARTESIAN_POINT('',(300.,-150.529169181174,193.207199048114));
#554=CARTESIAN_POINT('',(300.,-149.521671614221,193.595959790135));
#555=CARTESIAN_POINT('',(300.,-148.000841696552,194.152832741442));
#556=CARTESIAN_POINT('',(300.,-147.492295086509,194.334081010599));
#557=CARTESIAN_POINT('',(300.,-146.471991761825,194.687324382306));
#558=CARTESIAN_POINT('',(300.,-145.960235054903,194.859319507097));
#559=CARTESIAN_POINT('',(300.,-144.933972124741,195.193432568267));
#560=CARTESIAN_POINT('',(300.,-144.419468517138,195.355558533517));
#561=CARTESIAN_POINT('',(300.,-143.387339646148,195.669561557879));
#562=CARTESIAN_POINT('',(300.,-142.869714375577,195.821438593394));
#563=CARTESIAN_POINT('',(300.,-141.831546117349,196.114795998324));
#564=CARTESIAN_POINT('',(300.,-141.311003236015,196.256276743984));
#565=CARTESIAN_POINT('',(300.,-140.267213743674,196.528849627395));
#566=CARTESIAN_POINT('',(300.,-139.743967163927,196.659941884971));
#567=CARTESIAN_POINT('',(300.,-138.550310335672,196.946456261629));
#568=CARTESIAN_POINT('',(300.,-137.879114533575,197.098616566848));
#569=CARTESIAN_POINT('',(300.,-136.533148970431,197.386055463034));
#570=CARTESIAN_POINT('',(300.,-135.858379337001,197.521334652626));
#571=CARTESIAN_POINT('',(300.,-134.505254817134,197.775192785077));
#572=CARTESIAN_POINT('',(300.,-133.826897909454,197.893760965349));
#573=CARTESIAN_POINT('',(300.,-132.467493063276,198.114237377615));
#574=CARTESIAN_POINT('',(300.,-131.786445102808,198.21614547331));
#575=CARTESIAN_POINT('',(300.,-129.739408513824,198.497217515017));
#576=CARTESIAN_POINT('',(300.,-128.36994635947,198.65165088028));
#577=CARTESIAN_POINT('',(300.,-125.625518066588,198.896537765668));
#578=CARTESIAN_POINT('',(300.,-124.250552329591,198.986995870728));
#579=CARTESIAN_POINT('',(300.,-121.489812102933,199.106930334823));
#580=CARTESIAN_POINT('',(300.,-120.104021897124,199.13604156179));
#581=CARTESIAN_POINT('',(300.,-117.332902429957,199.135304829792));
#582=CARTESIAN_POINT('',(300.,-115.947573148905,199.105473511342));
#583=CARTESIAN_POINT('',(300.,-113.179333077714,198.990317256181));
#584=CARTESIAN_POINT('',(300.,-111.796422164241,198.904995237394));
#585=CARTESIAN_POINT('',(300.,-109.035019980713,198.682497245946));
#586=CARTESIAN_POINT('',(300.,-107.656528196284,198.545327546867));
#587=CARTESIAN_POINT('',(300.,-104.093300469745,198.127644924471));
#588=CARTESIAN_POINT('',(300.,-101.912829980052,197.810310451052));
#589=CARTESIAN_POINT('',(300.,-97.5693336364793,197.068386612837));
#590=CARTESIAN_POINT('',(300.,-95.4063179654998,196.643738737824));
#591=CARTESIAN_POINT('',(300.,-91.0986541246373,195.700766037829));
#592=CARTESIAN_POINT('',(300.,-88.9540269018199,195.182346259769));
#593=CARTESIAN_POINT('',(300.,-84.684443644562,194.064589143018));
#594=CARTESIAN_POINT('',(300.,-82.5595032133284,193.465192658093));
#595=CARTESIAN_POINT('',(300.,-78.330741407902,192.197465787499));
#596=CARTESIAN_POINT('',(300.,-76.2269170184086,191.529145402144));
#597=CARTESIAN_POINT('',(300.,-72.0292801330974,190.1305685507));
#598=CARTESIAN_POINT('',(300.,-69.9355584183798,189.400040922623));
#599=CARTESIAN_POINT('',(300.,-65.7681474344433,187.889547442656));
#600=CARTESIAN_POINT('',(300.,-63.6944424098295,187.109624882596));
#601=CARTESIAN_POINT('',(300.,-59.5642231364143,185.508119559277));
#602=CARTESIAN_POINT('',(300.,-57.5077021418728,184.686554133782));
#603=CARTESIAN_POINT('',(300.,-53.4093784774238,183.008626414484));
#604=CARTESIAN_POINT('',(300.,-51.3675732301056,182.15227039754));
#605=CARTESIAN_POINT('',(300.,-47.2965163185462,180.410858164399));
#606=CARTESIAN_POINT('',(300.,-45.2672633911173,179.525804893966));
#607=CARTESIAN_POINT('',(300.,-41.3699259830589,177.799126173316));
#608=CARTESIAN_POINT('',(300.,-39.5010968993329,176.959177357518));
#609=CARTESIAN_POINT('',(300.,-35.7708071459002,175.263056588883));
#610=CARTESIAN_POINT('',(300.,-33.9093465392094,174.406884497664));
#611=CARTESIAN_POINT('',(300.,-30.1922438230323,172.681694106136));
#612=CARTESIAN_POINT('',(300.,-28.3366021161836,171.812674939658));
#613=CARTESIAN_POINT('',(300.,-24.6298983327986,170.064949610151));
#614=CARTESIAN_POINT('',(300.,-22.7788362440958,169.186243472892));
#615=CARTESIAN_POINT('',(300.,-19.0795250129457,167.421747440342));
#616=CARTESIAN_POINT('',(300.,-17.2312766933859,166.535955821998));
#617=CARTESIAN_POINT('',(300.,-13.5368313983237,164.760107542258));
#618=CARTESIAN_POINT('',(300.,-11.6906344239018,163.870050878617));
#619=CARTESIAN_POINT('',(300.,-7.99859749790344,162.087830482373));
#620=CARTESIAN_POINT('',(300.,-6.15275780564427,161.195666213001));
#621=CARTESIAN_POINT('',(300.,-2.46087846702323,159.411751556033));
#622=CARTESIAN_POINT('',(300.,-0.614838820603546,158.520001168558));
#623=CARTESIAN_POINT('',(300.,4.92625670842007,155.848086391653));
#624=CARTESIAN_POINT('',(300.,8.62318651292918,154.071793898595));
#625=CARTESIAN_POINT('',(300.,16.0445277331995,150.538783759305));
#626=CARTESIAN_POINT('',(300.,19.7689899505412,148.782172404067));
#627=CARTESIAN_POINT('',(300.,27.2376053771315,145.311766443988));
#628=CARTESIAN_POINT('',(300.,30.9817574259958,143.597969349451));
#629=CARTESIAN_POINT('',(300.,38.4953317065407,140.229827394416));
#630=CARTESIAN_POINT('',(300.,42.2647449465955,138.575462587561));
#631=CARTESIAN_POINT('',(300.,47.9425356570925,136.151477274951));
#632=CARTESIAN_POINT('',(300.,49.8387022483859,135.353227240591));
#633=CARTESIAN_POINT('',(300.,53.6399120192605,133.77817048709));
#634=CARTESIAN_POINT('',(300.,55.5449551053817,133.00136354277));
#635=CARTESIAN_POINT('',(300.,59.3643062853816,131.471843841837));
#636=CARTESIAN_POINT('',(300.,61.2786126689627,130.719126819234));
#637=CARTESIAN_POINT('',(300.,65.1174881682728,129.240386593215));
#638=CARTESIAN_POINT('',(300.,67.0420571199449,128.514362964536));
#639=CARTESIAN_POINT('',(300.,70.8528569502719,127.110143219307));
#640=CARTESIAN_POINT('',(300.,72.7388118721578,126.431199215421));
#641=CARTESIAN_POINT('',(300.,76.5218699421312,125.104455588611));
#642=CARTESIAN_POINT('',(300.,78.4189741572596,124.456659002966));
#643=CARTESIAN_POINT('',(300.,82.2249745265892,123.195542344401));
#644=CARTESIAN_POINT('',(300.,84.1338725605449,122.582227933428));
#645=CARTESIAN_POINT('',(300.,87.9642096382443,121.393743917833));
#646=CARTESIAN_POINT('',(300.,89.885652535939,120.818586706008));
#647=CARTESIAN_POINT('',(300.,93.7419670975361,119.710519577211));
#648=CARTESIAN_POINT('',(300.,95.6768461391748,119.177635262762));
#649=CARTESIAN_POINT('',(300.,99.5610589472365,118.158661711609));
#650=CARTESIAN_POINT('',(300.,101.510405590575,117.672621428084));
#651=CARTESIAN_POINT('',(300.,105.383783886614,116.763031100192));
#652=CARTESIAN_POINT('',(300.,107.307571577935,116.33845044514));
#653=CARTESIAN_POINT('',(300.,110.202536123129,115.745555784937));
#654=CARTESIAN_POINT('',(300.,111.169232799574,115.555225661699));
#655=CARTESIAN_POINT('',(300.,113.105602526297,115.190299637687));
#656=CARTESIAN_POINT('',(300.,114.075275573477,115.015703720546));
#657=CARTESIAN_POINT('',(300.,116.016848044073,114.683502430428));
#658=CARTESIAN_POINT('',(300.,116.988745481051,114.525885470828));
#659=CARTESIAN_POINT('',(300.,118.93531645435,114.22877306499));
#660=CARTESIAN_POINT('',(300.,119.909990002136,114.089277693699));
#661=CARTESIAN_POINT('',(300.,121.86077487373,113.829971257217));
#662=CARTESIAN_POINT('',(300.,122.836883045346,113.710136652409));
#663=CARTESIAN_POINT('',(300.,124.302795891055,113.546173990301));
#664=CARTESIAN_POINT('',(300.,124.791726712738,113.494151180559));
#665=CARTESIAN_POINT('',(300.,125.770142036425,113.39558071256));
#666=CARTESIAN_POINT('',(300.,126.259626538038,113.349033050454));
#667=CARTESIAN_POINT('',(300.,127.238585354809,113.26168618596));
#668=CARTESIAN_POINT('',(300.,127.728059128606,113.220880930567));
#669=CARTESIAN_POINT('',(300.,128.707461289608,113.145181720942));
#670=CARTESIAN_POINT('',(300.,129.19738967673,113.110287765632));
#671=CARTESIAN_POINT('',(300.,130.667760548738,113.014508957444));
#672=CARTESIAN_POINT('',(300.,131.648798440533,112.962526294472));
#673=CARTESIAN_POINT('',(300.,133.611349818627,112.882486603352));
#674=CARTESIAN_POINT('',(300.,134.592862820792,112.854417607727));
#675=CARTESIAN_POINT('',(300.,136.556259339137,112.822160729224));
#676=CARTESIAN_POINT('',(300.,137.538142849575,112.817972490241));
#677=CARTESIAN_POINT('',(300.,139.938150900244,112.836754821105));
#678=CARTESIAN_POINT('',(300.,141.356192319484,112.872624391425));
#679=CARTESIAN_POINT('',(300.,144.191116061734,112.9928975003));
#680=CARTESIAN_POINT('',(300.,145.607997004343,113.077333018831));
#681=CARTESIAN_POINT('',(300.,148.439031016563,113.293013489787));
#682=CARTESIAN_POINT('',(300.,149.85318193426,113.424286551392));
#683=CARTESIAN_POINT('',(300.,152.677236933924,113.731155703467));
#684=CARTESIAN_POINT('',(300.,154.087138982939,113.906770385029));
#685=CARTESIAN_POINT('',(300.,156.901268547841,114.299081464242));
#686=CARTESIAN_POINT('',(300.,158.305495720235,114.515780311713));
#687=CARTESIAN_POINT('',(300.,161.106923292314,114.986308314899));
#688=CARTESIAN_POINT('',(300.,162.504126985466,115.240117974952));
#689=CARTESIAN_POINT('',(300.,165.315773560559,115.785234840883));
#690=CARTESIAN_POINT('',(300.,166.730106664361,116.077105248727));
#691=CARTESIAN_POINT('',(300.,169.55161587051,116.689787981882));
#692=CARTESIAN_POINT('',(300.,170.958795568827,117.010583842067));
#693=CARTESIAN_POINT('',(300.,173.76734653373,117.676040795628));
#694=CARTESIAN_POINT('',(300.,175.168718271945,118.020699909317));
#695=CARTESIAN_POINT('',(300.,177.967046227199,118.728635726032));
#696=CARTESIAN_POINT('',(300.,179.364001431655,119.091916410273));
#697=CARTESIAN_POINT('',(300.,182.154915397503,119.831750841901));
#698=CARTESIAN_POINT('',(300.,183.548872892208,120.208309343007));
#699=CARTESIAN_POINT('',(300.,186.33521398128,120.969343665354));
#700=CARTESIAN_POINT('',(300.,187.727596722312,121.35382259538));
#701=CARTESIAN_POINT('',(300.,191.161791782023,122.305379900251));
#702=CARTESIAN_POINT('',(300.,193.203208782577,122.873877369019));
#703=CARTESIAN_POINT('',(300.,197.28903708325,124.000088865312));
#704=CARTESIAN_POINT('',(300.,199.333448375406,124.557802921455));
#705=CARTESIAN_POINT('',(300.,203.428301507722,125.647239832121));
#706=CARTESIAN_POINT('',(300.,205.478740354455,126.178973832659));
#707=CARTESIAN_POINT('',(300.,209.588274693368,127.20284472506));
#708=CARTESIAN_POINT('',(300.,211.647364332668,127.695004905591));
#709=CARTESIAN_POINT('',(300.,215.776344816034,128.62802921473));
#710=CARTESIAN_POINT('',(300.,217.846230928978,129.068914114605));
#711=CARTESIAN_POINT('',(300.,221.998438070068,129.889747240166));
#712=CARTESIAN_POINT('',(300.,224.080760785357,130.269686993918));
#713=CARTESIAN_POINT('',(300.,228.22316339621,130.955148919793));
#714=CARTESIAN_POINT('',(300.,230.283059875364,131.261773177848));
#715=CARTESIAN_POINT('',(300.,234.414127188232,131.803225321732));
#716=CARTESIAN_POINT('',(300.,236.485306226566,132.037990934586));
#717=CARTESIAN_POINT('',(300.,240.635796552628,132.432061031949));
#718=CARTESIAN_POINT('',(300.,242.71511107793,132.591331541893));
#719=CARTESIAN_POINT('',(300.,246.878617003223,132.832759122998));
#720=CARTESIAN_POINT('',(300.,248.962809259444,132.914901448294));
#721=CARTESIAN_POINT('',(300.,253.132722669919,133.002143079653));
#722=CARTESIAN_POINT('',(300.,255.218443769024,133.007245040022));
#723=CARTESIAN_POINT('',(300.,259.387992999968,132.941898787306));
#724=CARTESIAN_POINT('',(300.,261.471821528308,132.871475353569));
#725=CARTESIAN_POINT('',(300.,265.648458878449,132.656969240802));
#726=CARTESIAN_POINT('',(300.,267.741244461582,132.512437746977));
#727=CARTESIAN_POINT('',(300.,271.920450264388,132.152796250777));
#728=CARTESIAN_POINT('',(300.,274.006871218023,131.937694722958));
#729=CARTESIAN_POINT('',(300.,278.171942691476,131.440654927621));
#730=CARTESIAN_POINT('',(300.,280.250592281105,131.158708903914));
#731=CARTESIAN_POINT('',(300.,284.398756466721,130.531958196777));
#732=CARTESIAN_POINT('',(300.,286.468269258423,130.187141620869));
#733=CARTESIAN_POINT('',(300.,290.596817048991,129.438746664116));
#734=CARTESIAN_POINT('',(300.,292.655850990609,129.03516247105));
#735=CARTESIAN_POINT('',(300.,296.762103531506,128.173364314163));
#736=CARTESIAN_POINT('',(300.,298.809323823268,127.715158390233));
#737=CARTESIAN_POINT('',(300.,302.923594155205,126.740410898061));
#738=CARTESIAN_POINT('',(300.,304.990454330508,126.223069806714));
#739=CARTESIAN_POINT('',(300.,309.110801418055,125.140036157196));
#740=CARTESIAN_POINT('',(300.,311.164292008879,124.574357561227));
#741=CARTESIAN_POINT('',(300.,315.258151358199,123.398202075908));
#742=CARTESIAN_POINT('',(300.,317.29852143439,122.787729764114));
#743=CARTESIAN_POINT('',(300.,321.366319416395,121.525309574));
#744=CARTESIAN_POINT('',(300.,323.393747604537,120.873362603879));
#745=CARTESIAN_POINT('',(300.,327.435771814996,119.531100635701));
#746=CARTESIAN_POINT('',(300.,329.450368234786,118.840786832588));
#747=CARTESIAN_POINT('',(300.,333.466787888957,117.424696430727));
#748=CARTESIAN_POINT('',(300.,335.468612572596,116.698923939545));
#749=CARTESIAN_POINT('',(300.,338.750456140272,115.478336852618));
#750=CARTESIAN_POINT('',(300.,340.03406743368,114.993147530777));
#751=CARTESIAN_POINT('',(300.,342.596137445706,114.009788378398));
#752=CARTESIAN_POINT('',(300.,343.874596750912,113.51162007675));
#753=CARTESIAN_POINT('',(300.,346.42651540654,112.502894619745));
#754=CARTESIAN_POINT('',(300.,347.699975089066,111.992338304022));
#755=CARTESIAN_POINT('',(300.,350.242040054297,110.959394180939));
#756=CARTESIAN_POINT('',(300.,351.510645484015,110.437006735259));
#757=CARTESIAN_POINT('',(300.,354.043134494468,109.380929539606));
#758=CARTESIAN_POINT('',(300.,355.30701809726,108.847239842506));
#759=CARTESIAN_POINT('',(300.,357.808050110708,107.778518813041));
#760=CARTESIAN_POINT('',(300.,359.045278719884,107.243675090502));
#761=CARTESIAN_POINT('',(300.,361.515402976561,106.164015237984));
#762=CARTESIAN_POINT('',(300.,362.748298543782,105.619198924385));
#763=CARTESIAN_POINT('',(300.,365.209851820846,104.520025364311));
#764=CARTESIAN_POINT('',(300.,366.438509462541,103.96566796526));
#765=CARTESIAN_POINT('',(300.,368.891673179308,102.847825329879));
#766=CARTESIAN_POINT('',(300.,370.116179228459,102.284340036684));
#767=CARTESIAN_POINT('',(300.,372.561117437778,101.148630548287));
#768=CARTESIAN_POINT('',(300.,373.78154963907,100.576406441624));
#769=CARTESIAN_POINT('',(300.,375.,100.));
#770=B_SPLINE_CURVE_WITH_KNOTS('',3,(#462,#463,#464,#465,#466,#467,#468,#469,#470,#471,#472,
#473,#474,#475,#476,#477,#478,#479,#480,#481,#482,#483,#484,#485,#486,#487,#488,#489,#490,#491,
#492,#493,#494,#495,#496,#497,#498,#499,#500,#501,#502,#503,#504,#505,#506,#507,#508,#509,#510,
#511,#512,#513,#514,#515,#516,#517,#518,#519,#520,#521,#522,#523,#524,#525,#526,#527,#528,#529,
#530,#531,#532,#533,#534,#535,#536,#537,#538,#539,#540,#541,#542,#543,#544,#545,#546,#547,#548,
#549,#550,#551,#552,#553,#554,#555,#556,#557,#558,#559,#560,#561,#562,#563,#564,#565,#566,#567,
#568,#569,#570,#571,#572,#573,#574,#575,#576,#577,#578,#579,#580,#581,#582,#583,#584,#585,#586,
#587,#588,#589,#590,#591,#592,#593,#594,#595,#596,#597,#598,#599,#600,#601,#602,#603,#604,#605,
#606,#607,#608,#609,#610,#611,#612,#613,#614,#615,#616,#617,#618,#619,#620,#621,#622,#623,#624,
#625,#626,#627,#628,#629,#630,#631,#632,#633,#634,#635,#636,#637,#638,#639,#640,#641,#642,#643,
#644,#645,#646,#647,#648,#649,#650,#651,#652,#653,#654,#655,#656,#657,#658,#659,#660,#661,#662,
#663,#664,#665,#666,#667,#668,#669,#670,#671,#672,#673,#674,#675,#676,#677,#678,#679,#680,#681,
#682,#683,#684,#685,#686,#687,#688,#689,#690,#691,#692,#693,#694,#695,#696,#697,#698,#699,#700,
#701,#702,#703,#704,#705,#706,#707,#708,#709,#710,#711,#712,#713,#714,#715,#716,#717,#718,#719,
#720,#721,#722,#723,#724,#725,#726,#727,#728,#729,#730,#731,#732,#733,#734,#735,#736,#737,#738,
#739,#740,#741,#742,#743,#744,#745,#746,#747,#748,#749,#750,#751,#752,#753,#754,#755,#756,#757,
#758,#759,#760,#761,#762,#763,#764,#765,#766,#767,#768,#769),.UNSPECIFIED.,.F.,.F.,(4,2,2,2,2,2,
2,2,2,2,2,2,2,2,2,2,2,2,2,2,2,2,2,2,2,2,2,2,2,2,2,2,2,2,2,2,2,2,2,2,2,2,2,2,2,2,2,2,2,2,2,2,2,2,
2,2,2,2,2,2,2,2,2,2,2,2,2,2,2,2,2,2,2,2,2,2,2,2,2,2,2,2,2,2,2,2,2,2,2,2,2,2,2,2,2,2,2,2,2,2,2,2,
2,2,2,2,2,2,2,2,2,2,2,2,2,2,2,2,2,2,2,2,2,2,2,2,2,2,2,2,2,2,2,2,2,2,2,2,2,2,2,2,2,2,2,2,2,2,2,2,
2,2,2,4),(0.,5.61123637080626,11.2255671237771,16.8417238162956,22.4587824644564,
28.0761279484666,33.6934078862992,39.2549214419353,44.8156667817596,50.3756397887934,
55.9349434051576,61.4937025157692,67.051972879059,73.7362097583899,80.4211994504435,
87.1071141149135,93.7934919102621,100.479049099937,107.166837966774,113.853732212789,
120.540554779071,127.227120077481,133.912217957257,142.685330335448,151.457722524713,
160.232408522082,169.010293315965,177.790551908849,182.201253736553,186.611953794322,
191.021722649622,195.431481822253,199.839321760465,204.24715814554,208.652916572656,
213.058694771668,217.464178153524,221.869599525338,225.138595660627,228.407545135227,
231.677260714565,234.946977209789,238.218657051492,241.490338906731,244.730960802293,
247.971604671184,251.210662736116,252.830229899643,254.449793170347,256.068020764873,
257.686252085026,259.30442481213,260.922578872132,262.987032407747,265.0514127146,
267.11711655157,269.182837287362,273.315556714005,277.447979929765,281.604930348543,
285.760707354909,289.916265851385,294.071321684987,300.67834919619,307.288986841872,
313.90635625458,320.528585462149,327.149855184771,333.80162995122,340.447653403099,
347.090932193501,353.733017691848,360.374423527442,366.521064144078,372.667757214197,
378.814866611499,384.961959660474,391.110595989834,397.259235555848,403.409660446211,
409.560087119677,421.864617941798,434.218210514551,446.571083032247,458.919770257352,
465.091685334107,471.263535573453,477.434286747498,483.604939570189,489.618021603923,
495.631688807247,501.646340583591,507.66293634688,513.683148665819,519.709585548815,
525.618940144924,528.574599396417,531.530255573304,534.483881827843,537.437520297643,
540.387596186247,541.862642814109,543.337688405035,544.81116733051,546.284645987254,
549.231574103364,552.17702657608,555.122435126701,559.377020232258,563.634410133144,
567.894359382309,572.156097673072,576.418090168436,580.677851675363,585.009895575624,
589.339488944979,593.668723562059,597.998887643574,602.33061807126,606.664082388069,
613.021378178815,619.378657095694,625.733184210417,632.083943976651,638.432122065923,
644.781181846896,651.027771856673,657.279759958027,663.534558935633,669.790553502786,
676.046332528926,682.300059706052,688.592116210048,694.883417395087,701.175448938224,
707.468671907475,713.762517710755,720.055438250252,726.446670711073,732.836063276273,
739.224803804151,745.613404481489,752.001806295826,758.389469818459,762.506150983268,
766.622349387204,770.738269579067,774.85406411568,778.969839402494,783.013447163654,
787.057129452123,791.100876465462,795.144648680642,799.188379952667),.UNSPECIFIED.);
#771=CARTESIAN_POINT('',(300.,-375.,100.));
#772=VERTEX_POINT('',#771);
#773=CARTESIAN_POINT('',(300.,375.,100.));
#774=VERTEX_POINT('',#773);
#775=EDGE_CURVE('E11',#772,#774,#770,.T.);
#776=CARTESIAN_POINT('',(-750.,-375.,100.));
#777=CARTESIAN_POINT('',(-644.685568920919,-375.,100.));
#778=CARTESIAN_POINT('',(-536.684515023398,-375.,100.));
#779=CARTESIAN_POINT('',(-355.235514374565,-375.,100.));
#780=CARTESIAN_POINT('',(-175.903454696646,-375.,100.));
#781=CARTESIAN_POINT('',(47.4554331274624,-375.,100.));
#782=CARTESIAN_POINT('',(285.091607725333,-375.,100.));
#783=CARTESIAN_POINT('',(500.445116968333,-375.,100.));
#784=CARTESIAN_POINT('',(669.085175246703,-375.,100.));
#785=CARTESIAN_POINT('',(750.,-375.,100.));
#786=B_SPLINE_CURVE_WITH_KNOTS('',3,(#776,#777,#778,#779,#780,#781,#782,#783,#784,#785),
.UNSPECIFIED.,.F.,.F.,(4,1,1,1,1,1,1,4),(0.,0.210628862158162,0.216002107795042,
0.362898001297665,0.569292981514,0.66271988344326,0.838170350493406,1.),.UNSPECIFIED.);
#787=EDGE_CURVE('E97',#772,#322,#786,.T.);
#788=CARTESIAN_POINT('',(750.,375.,100.));
#789=CARTESIAN_POINT('',(669.085175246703,375.,100.));
#790=CARTESIAN_POINT('',(500.445116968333,375.,100.));
#791=CARTESIAN_POINT('',(285.091607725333,375.,100.));
#792=CARTESIAN_POINT('',(47.4554331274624,375.,100.));
#793=CARTESIAN_POINT('',(-175.903454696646,375.,100.));
#794=CARTESIAN_POINT('',(-355.235514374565,375.,100.));
#795=CARTESIAN_POINT('',(-536.684515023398,375.,100.));
#796=CARTESIAN_POINT('',(-644.685568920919,375.,100.));
#797=CARTESIAN_POINT('',(-750.,375.,100.));
#798=B_SPLINE_CURVE_WITH_KNOTS('',3,(#788,#789,#790,#791,#792,#793,#794,#795,#796,#797),
.UNSPECIFIED.,.F.,.F.,(4,1,1,1,1,1,1,4),(0.,0.161829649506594,0.33728011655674,0.430707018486,
0.637101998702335,0.783997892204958,0.789371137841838,1.),.UNSPECIFIED.);
#799=EDGE_CURVE('E94',#320,#774,#798,.T.);
#800=ORIENTED_EDGE('',*,*,#775,.F.);
#801=ORIENTED_EDGE('',*,*,#787,.T.);
#802=ORIENTED_EDGE('',*,*,#323,.F.);
#803=ORIENTED_EDGE('',*,*,#799,.T.);
#804=EDGE_LOOP('',(#800,#801,#802,#803));
#805=FACE_BOUND('',#804,.T.);
#806=ADVANCED_FACE('F110',(#805),#461,.F.);
#807=CARTESIAN_POINT('',(-750.,375.,253.111113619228));
#808=DIRECTION('',(0.,-1.,0.));
#809=DIRECTION('',(0.,0.,-1.));
#810=AXIS2_PLACEMENT_3D('',#807,#808,#809);
#811=PLANE('',#810);
#812=DIRECTION('',(0.,0.,-1.));
#813=VECTOR('',#812,1.);
#814=CARTESIAN_POINT('',(300.,375.,253.120113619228));
#815=LINE('',#814,#813);
#816=EDGE_CURVE('E154',#774,#368,#815,.T.);
#817=ORIENTED_EDGE('',*,*,#816,.F.);
#818=ORIENTED_EDGE('',*,*,#799,.F.);
#819=ORIENTED_EDGE('',*,*,#345,.T.);
#820=ORIENTED_EDGE('',*,*,#375,.T.);
#821=EDGE_LOOP('',(#817,#818,#819,#820));
#822=FACE_BOUND('',#821,.T.);
#823=ADVANCED_FACE('F121',(#822),#811,.F.);
#824=CARTESIAN_POINT('',(-750.,-375.,253.111113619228));
#825=DIRECTION('',(0.,1.,0.));
#826=DIRECTION('',(0.,0.,1.));
#827=AXIS2_PLACEMENT_3D('',#824,#825,#826);
#828=PLANE('',#827);
#829=DIRECTION('',(0.,0.,-1.));
#830=VECTOR('',#829,1.);
#831=CARTESIAN_POINT('',(300.,-375.,253.120113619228));
#832=LINE('',#831,#830);
#833=EDGE_CURVE('E56',#772,#360,#832,.T.);
#834=ORIENTED_EDGE('',*,*,#833,.T.);
#835=ORIENTED_EDGE('',*,*,#361,.T.);
#836=ORIENTED_EDGE('',*,*,#331,.F.);
#837=ORIENTED_EDGE('',*,*,#787,.F.);
#838=EDGE_LOOP('',(#834,#835,#836,#837));
#839=FACE_BOUND('',#838,.T.);
#840=ADVANCED_FACE('F37',(#839),#828,.F.);
#841=CARTESIAN_POINT('',(300.,375.,253.120113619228));
#842=DIRECTION('',(-1.,0.,0.));
#843=DIRECTION('',(0.,-1.,0.));
#844=AXIS2_PLACEMENT_3D('',#841,#842,#843);
#845=PLANE('',#844);
#846=ORIENTED_EDGE('',*,*,#775,.T.);
#847=ORIENTED_EDGE('',*,*,#816,.T.);
#848=ORIENTED_EDGE('',*,*,#369,.F.);
#849=ORIENTED_EDGE('',*,*,#833,.F.);
#850=EDGE_LOOP('',(#846,#847,#848,#849));
#851=FACE_BOUND('',#850,.T.);
#852=ADVANCED_FACE('F145',(#851),#845,.T.);
#853=CLOSED_SHELL('',(#349,#380,#806,#823,#840,#852));
#854=MANIFOLD_SOLID_BREP('B2',#853);
#855=ADVANCED_BREP_SHAPE_REPRESENTATION('',(#18,#854),#14);
#856=SHAPE_DEFINITION_REPRESENTATION(#9,#855);
ENDSEC;
END-ISO-10303-21;
